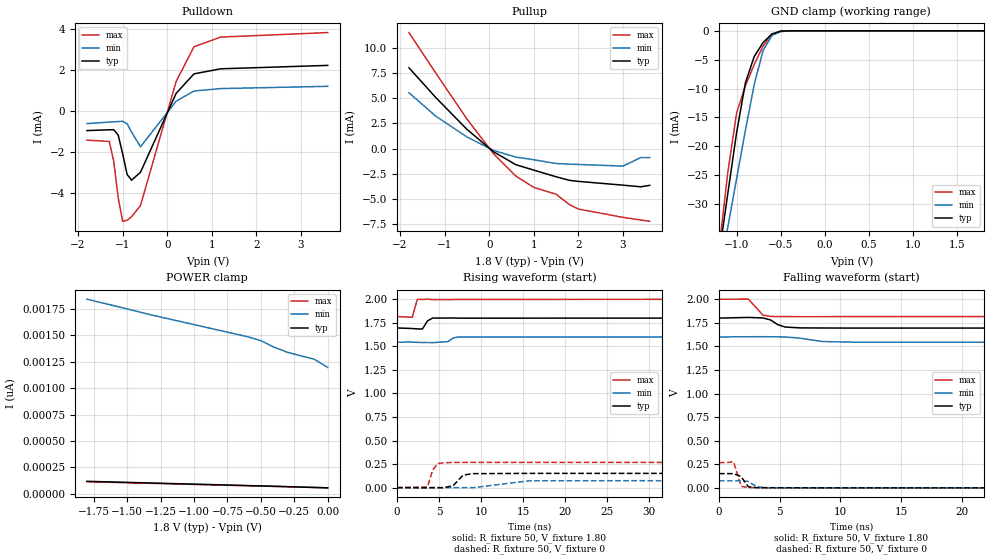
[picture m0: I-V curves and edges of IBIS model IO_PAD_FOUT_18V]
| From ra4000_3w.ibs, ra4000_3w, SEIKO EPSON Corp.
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[Model]   IO_PAD_FOUT_18V
Model_type 3-state
Enable Active-High
Polarity Non-Inverting
Vmeas=0.90
C_comp   2.5p   2.0p   3.0p
[Temperature Range] 25   125   -40
[Voltage Range]   1.80   1.60   2.00
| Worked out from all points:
|   slope of the pulldown table from 0 to 0.27 V, typ, clamps not added: 249 ohm
|   slope of the pullup table from 0 to 0.27 V, typ, clamps not added: 325 ohm
|   GND clamp passes 1 mA (typ) near -0.63 V on its own axis
|   falling waveform, R_fixture 50, V_fixture 1.80: 20-80 % time 939ps typ, 1.63ns min, 787ps max; typ from 1.8 V to 1.7 V
|   falling waveform, R_fixture 50, V_fixture 0: 20-80 % time 512ps typ, 605ps min, 376ps max; typ from 0.151 V to 0 V
|   rising waveform, R_fixture 50, V_fixture 1.80: 20-80 % time 568ps typ, 603ps min, 351ps max; typ from 1.7 V to 1.8 V
|   rising waveform, R_fixture 50, V_fixture 0: 20-80 % time 925ps typ, 1.58ns min, 705ps max; typ from 0 V to 0.151 V
[Pullup]
-1.8V     8.019mA    5.543mA    11.52mA
-1.2V     5.073mA    3.223mA    7.502mA
-500mV    1.91mA     1.152mA    2.939mA
100mV     -328.1uA   -184uA     -533.3uA
600mV     -1.606mA   -849uA     -2.738mA
1V        -2.14mA    -1.11mA    -3.857mA
1.5V      -2.802mA   -1.485mA   -4.534mA
1.8V      -3.153mA   -1.545mA   -5.569mA
2V        -3.258mA   -1.577mA   -6.004mA
3V        -3.633mA   -1.74mA    -6.831mA
3.4V      -3.796mA   -893.1uA   -7.094mA
3.6V      -3.649mA   -897.2uA   -7.222mA
[Pulldown]
-1.8V     -961.6uA   -619.2uA   -1.43mA
-1.3V     -922.8uA   -548.5uA   -1.492mA
-1.2V     -918.1uA   -534.5uA   -2.462mA
-1.1V     -1.178mA   -521.4uA   -4.238mA
-1V       -2.093mA   -509.6uA   -5.388mA
-900mV    -3.101mA   -625.5uA   -5.336mA
-800mV    -3.382mA   -1.035mA   -5.164mA
-600mV    -2.995mA   -1.753mA   -4.62mA
200mV     855.8uA    473.6uA    1.436mA
600mV     1.806mA    969.1uA    3.13mA
1.2V      2.053mA    1.088mA    3.601mA
3.6V      2.219mA    1.198mA    3.821mA
[GND Clamp]
-1.8V     -104.1mA   -95.66mA   -119.4mA
-1.2V     -38.93mA   -42.42mA   -37.91mA
-1.1V     -28.21mA   -33.99mA   -24.53mA
-1V       -17.61mA   -25.59mA   -14.2mA
-900mV    -8.983mA   -17.21mA   -9.508mA
-800mV    -4.448mA   -9.271mA   -5.815mA
-700mV    -2.032mA   -3.421mA   -2.638mA
-600mV    -545.3uA   -803.9uA   -605.9uA
-500mV    -56.89uA   -135.5uA   -35.53uA
-400mV    -3.147uA   -16.88uA   -734nA
1.8V      55.75pA    1.305nA    49.44pA
[POWER Clamp]
-1.8V     117.7pA    1.843nA    113.8pA
-1.3V     100.9pA    1.688nA    97.89pA
-600mV    77.54pA    1.487nA    75.68pA
-500mV    74.22pA    1.45nA     72.54pA
-400mV    70.76pA    1.387nA    69.39pA
-300mV    67.06pA    1.339nA    66.03pA
-100mV    59.63pA    1.273nA    59.28pA
0V        55.75pA    1.196nA    56.02pA
[Falling Waveform]
R_fixture=50
V_fixture=1.80
V_fixture_min=1.60
V_fixture_max=2.00
0s        1.8V       1.6V       2V
2.424ns   1.807V     1.602V     2.001V
3.636ns   1.801V     1.603V     1.83V
4.242ns   1.781V     1.601V     1.818V
4.848ns   1.73V      1.601V     1.816V
5.455ns   1.705V     1.6V       1.816V
6.667ns   1.696V     1.587V     1.815V
8.485ns   1.695V     1.552V     1.815V
10.91ns   1.694V     1.545V     1.816V
60ns      1.695V     1.544V     1.816V
[Falling Waveform]
R_fixture=50
V_fixture=0
V_fixture_min=0
V_fixture_max=0
0s        151.3mV    74.58mV    268mV
606.1ps   151.3mV    74.58mV    268mV
1.212ns   150.2mV    74.11mV    276.4mV
1.818ns   120.5mV    75.52mV    17.16mV
2.424ns   11.75mV    67.69mV    3.281mV
3.03ns    2.019mV    17.03mV    2.406mV
3.636ns   1.673mV    3.601mV    877.3uV
4.242ns   1.65mV     961.3uV    511.9uV
8.485ns   137.4uV    266.8uV    114.7uV
60ns      5.887uV    7.49uV     2.333uV
[Rising Waveform]
R_fixture=50
V_fixture=1.80
V_fixture_min=1.60
V_fixture_max=2.00
0s        1.695V     1.544V     1.816V
1.818ns   1.689V     1.545V     1.808V
2.424ns   1.685V     1.542V     1.999V
3.03ns    1.684V     1.541V     1.998V
3.636ns   1.77V      1.54V      2.001V
4.242ns   1.8V       1.539V     1.996V
6.061ns   1.8V       1.55V      1.997V
6.667ns   1.801V     1.587V     1.997V
7.273ns   1.799V     1.6V       1.998V
60ns      1.8V       1.6V       2V
[Rising Waveform]
R_fixture=50
V_fixture=0
V_fixture_min=0
V_fixture_max=0
0s        599pV      3.375nV    549pV
3.636ns   -2.591mV   38.29uV    7.967mV
4.242ns   23.5uV     28.61uV    184.9mV
4.848ns   -236.5uV   22.69uV    254.8mV
5.455ns   -833.2uV   -56.8uV    262.8mV
6.667ns   17.93mV    -1.272mV   266.7mV
7.879ns   133.3mV    9.801uV    267.6mV
9.091ns   148.2mV    -251uV     267.8mV
15.76ns   151.2mV    72.64mV    267.9mV
60ns      151.3mV    74.58mV    268mV
[Ramp]
R_load=50
dV/dt_r   9.075E-2/8.430E-10   4.475E-2/1.515E-9   1.608E-1/4.792E-10
dV/dt_f   6.318E-2/8.647E-10   3.338E-2/1.578E-9   1.106E-1/5.057E-10
|[End   IO_PAD_FOUT_18V
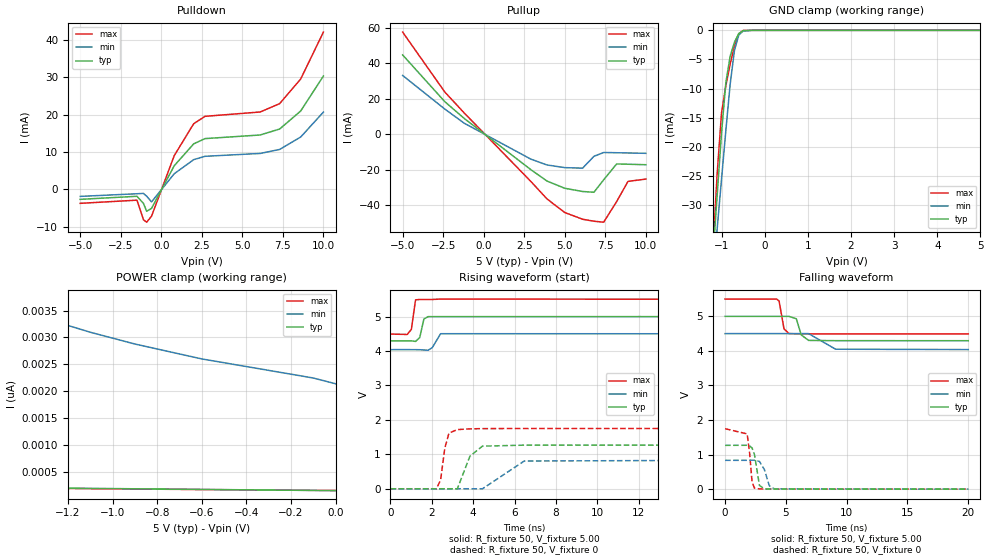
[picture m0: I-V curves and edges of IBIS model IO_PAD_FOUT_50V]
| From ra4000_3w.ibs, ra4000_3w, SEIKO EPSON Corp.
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[Model]   IO_PAD_FOUT_50V
Model_type 3-state
Enable Active-High
Polarity Non-Inverting
Vmeas=2.50
C_comp   2.5p   2.0p   3.0p
[Temperature Range] 25   125   -40
[Voltage Range]   5.00   4.50   5.50
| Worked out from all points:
|   slope of the pulldown table from 0 to 0.75 V, typ, clamps not added: 126 ohm
|   slope of the pullup table from 0 to 0.75 V, typ, clamps not added: 143 ohm
|   GND clamp passes 1 mA (typ) near -0.63 V on its own axis
|   falling waveform, R_fixture 50, V_fixture 5.00: 20-80 % time 401ps typ, 591ps min, 309ps max; typ from 5 V to 4.29 V
|   falling waveform, R_fixture 50, V_fixture 0: 20-80 % time 353ps typ, 464ps min, 298ps max; typ from 1.27 V to 0 V
|   rising waveform, R_fixture 50, V_fixture 5.00: 20-80 % time 158ps typ, 253ps min, 142ps max; typ from 4.29 V to 5 V
|   rising waveform, R_fixture 50, V_fixture 0: 20-80 % time 398ps typ, 603ps min, 283ps max; typ from 0 V to 1.27 V
[Pullup]
-5V       44.6mA     33.06mA    57.43mA
-2.4V     18.33mA    14.17mA    23.76mA
-1.2V     8.881mA    6.2mA      11.95mA
2.9V      -19.85mA   -13.95mA   -26.45mA
3.9V      -26.28mA   -17.26mA   -36.32mA
5V        -30.37mA   -18.76mA   -44mA
6.1V      -32.18mA   -19.06mA   -47.77mA
6.8V      -32.6mA    -12.39mA   -48.89mA
7.4V      -25.59mA   -10.25mA   -49.43mA
8.2V      -16.68mA   -10.39mA   -37.84mA
8.9V      -16.85mA   -10.51mA   -26.5mA
10V       -17.13mA   -10.72mA   -25.19mA
[Pulldown]
-5V       -2.695mA   -1.904mA   -3.76mA
-1.5V     -1.871mA   -1.196mA   -2.909mA
-1.1V     -3.756mA   -1.098mA   -8.145mA
-900mV    -5.868mA   -1.858mA   -8.805mA
-600mV    -5.116mA   -3.374mA   -7.202mA
800mV     6.302mA    4.159mA    9mA
2V        12.16mA    7.932mA    17.55mA
2.7V      13.56mA    8.824mA    19.52mA
6.1V      14.53mA    9.591mA    20.68mA
7.3V      16.12mA    10.66mA    22.91mA
8.6V      20.95mA    13.99mA    29.52mA
10V       30.3mA     20.65mA    42.06mA
[GND Clamp]
-5V       -507.1mA   -412.9mA   -622.2mA
-1.2V     -38.93mA   -42.42mA   -37.92mA
-1.1V     -28.22mA   -34mA      -24.54mA
-1V       -17.62mA   -25.59mA   -14.21mA
-900mV    -8.989mA   -17.22mA   -9.509mA
-800mV    -4.45mA    -9.278mA   -5.815mA
-700mV    -2.032mA   -3.427mA   -2.638mA
-600mV    -545.3uA   -804.8uA   -605.9uA
-500mV    -56.89uA   -135.5uA   -35.53uA
-300mV    -121.9nA   -1.69uA    -9.391nA
5V        151.4pA    2.52nA     136.9pA
[POWER Clamp]
-5V       441.4pA    19.15nA    8.229uA
-4.7V     412.4pA    16.71nA    4.235nA
-4.6V     403.3pA    15.96nA    343.3pA
-4.5V     394.5pA    15.24nA    298pA
-1.7V     219.2pA    3.963nA    206.5pA
-1.6V     214.7pA    3.794nA    203.4pA
-1.3V     201.7pA    3.349nA    193.8pA
-1.1V     193.4pA    3.097nA    187.4pA
-900mV    185.3pA    2.878nA    181pA
-600mV    173.6pA    2.601nA    171.5pA
-100mV    155.1pA    2.246nA    156.3pA
0V        151.4pA    2.139nA    153.5pA
[Falling Waveform]
R_fixture=50
V_fixture=5.00
V_fixture_min=4.50
V_fixture_max=5.50
0s        5V         4.5V       5.5V
4.242ns   5V         4.501V     5.5V
4.444ns   5V         4.5V       5.441V
4.848ns   5V         4.5V       4.638V
5.253ns   5V         4.5V       4.502V
5.859ns   4.93V      4.5V       4.494V
6.263ns   4.463V     4.5V       4.493V
6.869ns   4.304V     4.5V       4.493V
9.091ns   4.296V     4.049V     4.492V
20ns      4.295V     4.039V     4.492V
[Falling Waveform]
R_fixture=50
V_fixture=0
V_fixture_min=0
V_fixture_max=0
0s        1.268V     834.1mV    1.75V
1.818ns   1.27V      834.8mV    1.598V
2.02ns    1.252V     837mV      1.035V
2.222ns   1.192V     838.3mV    207.6mV
2.424ns   993.1mV    838.2mV    26.89mV
2.828ns   108.5mV    801.9mV    7.029mV
3.232ns   8.937mV    570.8mV    5.304mV
3.636ns   4.277mV    99.68mV    4.205mV
4.04ns    3.189mV    11.69mV    3.413mV
20ns      29.91uV    41.91uV    17.85uV
[Rising Waveform]
R_fixture=50
V_fixture=5.00
V_fixture_min=4.50
V_fixture_max=5.50
0s        4.295V     4.039V     4.492V
808.1ps   4.296V     4.04V      4.48V
1.01ns    4.293V     4.039V     4.626V
1.212ns   4.278V     4.039V     5.486V
1.414ns   4.389V     4.037V     5.495V
1.616ns   4.929V     4.029V     5.496V
1.818ns   4.997V     4.022V     5.497V
2.02ns    4.998V     4.097V     5.496V
2.424ns   4.998V     4.502V     5.508V
20ns      5V         4.5V       5.5V
[Rising Waveform]
R_fixture=50
V_fixture=0
V_fixture_min=0
V_fixture_max=0
0s        1.445nV    4.47nV     1.368nV
2.222ns   -891.5nV   -11.98mV   -1.444mV
2.424ns   48.18uV    -2.853mV   255.4mV
2.626ns   87.2uV     -183.6uV   1.179V
2.828ns   -294.4uV   -68.97uV   1.616V
3.232ns   -904uV     -22.36uV   1.718V
3.838ns   942.8mV    90.69uV    1.739V
4.444ns   1.237V     -999.9uV   1.746V
6.465ns   1.266V     805.1mV    1.749V
20ns      1.268V     834.1mV    1.75V
[Ramp]
R_load=50
dV/dt_r   7.608E-1/3.613E-10   5.004E-1/6.009E-10   1.050E+0/2.400E-10
dV/dt_f   4.228E-1/3.730E-10   2.767E-1/5.844E-10   6.049E-1/2.670E-10
|[End   IO_PAD_FOUT_50V
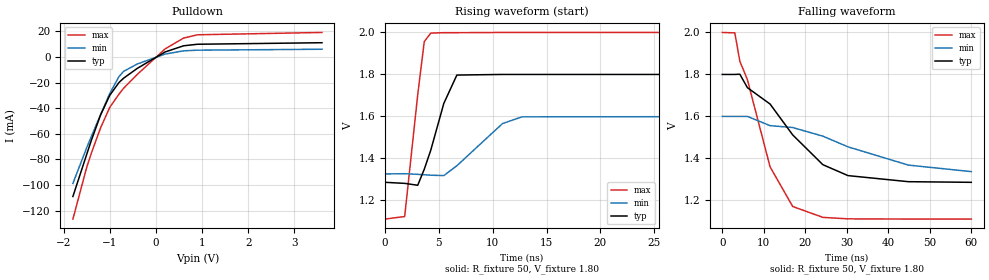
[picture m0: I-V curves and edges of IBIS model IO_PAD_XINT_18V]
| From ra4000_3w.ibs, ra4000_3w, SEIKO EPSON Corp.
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[Model]   IO_PAD_XINT_18V
Model_type Open_drain
Polarity Non-Inverting
Vref=2.0
Vmeas=0.9
Rref=5000
C_comp   2.5p   2.0p   3.0p
[Temperature Range] 25   125   -40
[Voltage Range]   1.80   1.60   2.00
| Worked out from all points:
|   slope of the pulldown table from 0 to 0.27 V, typ, clamps not added: 54.4 ohm
|   falling waveform, R_fixture 50, V_fixture 1.80: 20-80 % time 13.7ns typ, 23.5ns min, 7.76ns max; typ from 1.8 V to 1.29 V
|   rising waveform, R_fixture 50, V_fixture 1.80: 20-80 % time 1.8ns typ, 3.29ns min, 1.1ns max; typ from 1.29 V to 1.8 V
[Pulldown]
-1.8V     -108.9mA   -98.7mA    -126.5mA
-1.5V     -75.95mA   -70.76mA   -86.06mA
-1.4V     -65.08mA   -62.09mA   -75.07mA
-1.2V     -45.3mA    -45.03mA   -55.4mA
-1V       -29.91mA   -28.44mA   -39.28mA
-800mV    -19.93mA   -15.3mA    -29mA
-700mV    -16.58mA   -11.24mA   -24.44mA
-400mV    -8.853mA   -5.464mA   -13.51mA
200mV     3.863mA    2.205mA    6.265mA
600mV     8.675mA    4.737mA    14.69mA
900mV     9.873mA    5.241mA    17.26mA
3.6V      11.07mA    5.981mA    19.07mA
[Falling Waveform]
R_fixture=50
V_fixture=1.80
V_fixture_min=1.60
V_fixture_max=2.00
0s        1.8V       1.6V       2V
3.03ns    1.8V       1.6V       1.998V
4.242ns   1.801V     1.6V       1.863V
6.061ns   1.737V     1.6V       1.775V
11.52ns   1.659V     1.556V     1.36V
16.97ns   1.512V     1.547V     1.171V
24.24ns   1.37V      1.506V     1.119V
30.3ns    1.318V     1.455V     1.112V
44.85ns   1.289V     1.368V     1.111V
60ns      1.286V     1.337V     1.111V
[Rising Waveform]
R_fixture=50
V_fixture=1.80
V_fixture_min=1.60
V_fixture_max=2.00
0s        1.286V     1.326V     1.111V
1.818ns   1.281V     1.327V     1.123V
3.03ns    1.272V     1.324V     1.703V
3.636ns   1.348V     1.322V     1.956V
4.242ns   1.439V     1.32V      1.997V
5.455ns   1.662V     1.318V     1.999V
6.667ns   1.797V     1.365V     1.999V
10.91ns   1.8V       1.566V     2V
12.73ns   1.8V       1.598V     2V
60ns      1.8V       1.6V       2V
[Ramp]
R_load=50
dV/dt_r   3.085E-1/1.825E-9   1.642E-1/3.454E-9   5.334E-1/1.080E-9
dV/dt_f   3.084E-1/1.367E-8   1.579E-1/2.351E-8   5.334E-1/7.707E-9
|[End   IO_PAD_XINT_18V
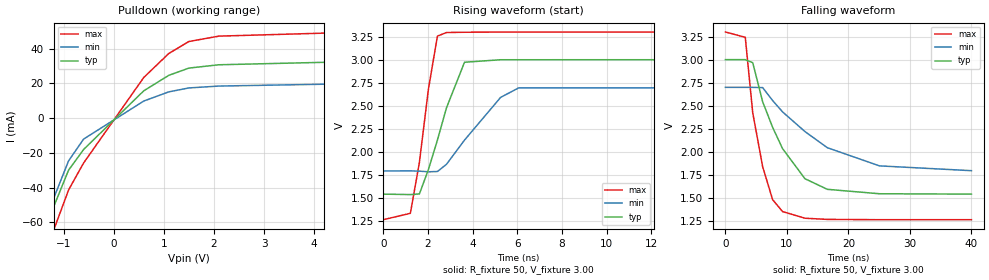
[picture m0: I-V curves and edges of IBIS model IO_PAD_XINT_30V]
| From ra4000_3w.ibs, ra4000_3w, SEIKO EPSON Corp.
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[Model]   IO_PAD_XINT_30V
Model_type Open_drain
Polarity Non-Inverting
Vref=3.3
Vmeas=1.5
Rref=5000
C_comp   2.5p   2.0p   3.0p
[Temperature Range] 25   125   -40
[Voltage Range]   3.00   2.70   3.30
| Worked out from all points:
|   slope of the pulldown table from 0 to 0.45 V, typ, clamps not added: 36.6 ohm
|   falling waveform, R_fixture 50, V_fixture 3.00: 20-80 % time 5.79ns typ, 10.4ns min, 2.99ns max; typ from 3 V to 1.54 V
|   rising waveform, R_fixture 50, V_fixture 3.00: 20-80 % time 1.08ns typ, 1.8ns min, 710ps max; typ from 1.54 V to 3 V
[Pulldown]
-3V       -260.3mA   -217.9mA   -314.6mA
-1.4V     -68.68mA   -63.46mA   -84.25mA
-1.3V     -59.72mA   -54.87mA   -74.25mA
-1.2V     -51.27mA   -46.4mA    -64.82mA
-900mV    -30mA      -24.64mA   -41.43mA
-600mV    -18.08mA   -12.07mA   -25.86mA
600mV     15.77mA    9.868mA    23.45mA
1.1V      24.7mA     15.17mA    37.31mA
1.5V      28.87mA    17.43mA    44.2mA
2.1V      30.79mA    18.51mA    47.31mA
5V        32.75mA    19.99mA    49.7mA
6V        34.91mA    21.45mA    52.66mA
[Falling Waveform]
R_fixture=50
V_fixture=3.00
V_fixture_min=2.70
V_fixture_max=3.30
0s        3V         2.7V       3.3V
3.232ns   3V         2.7V       3.242V
4.444ns   2.967V     2.7V       2.425V
6.061ns   2.543V     2.697V     1.839V
7.677ns   2.267V     2.557V     1.483V
9.293ns   2.036V     2.434V     1.354V
12.93ns   1.71V      2.221V     1.282V
16.57ns   1.595V     2.046V     1.269V
25.05ns   1.547V     1.849V     1.266V
40ns      1.543V     1.797V     1.266V
[Rising Waveform]
R_fixture=50
V_fixture=3.00
V_fixture_min=2.70
V_fixture_max=3.30
0s        1.543V     1.794V     1.266V
1.212ns   1.538V     1.795V     1.335V
1.616ns   1.545V     1.792V     1.886V
2.02ns    1.809V     1.785V     2.68V
2.424ns   2.129V     1.788V     3.255V
2.828ns   2.477V     1.866V     3.294V
3.636ns   2.972V     2.128V     3.297V
5.253ns   2.999V     2.591V     3.299V
6.061ns   2.999V     2.694V     3.299V
40ns      3V         2.7V       3.3V
[Ramp]
R_load=50
dV/dt_r   8.743E-1/1.061E-9   5.439E-1/1.833E-9   1.220E+0/6.505E-10
dV/dt_f   8.743E-1/5.792E-9   5.420E-1/1.038E-8   1.220E+0/2.997E-9
|[End   IO_PAD_XINT_30V
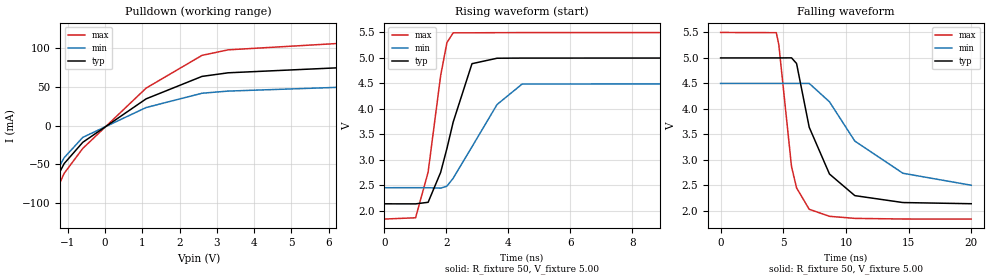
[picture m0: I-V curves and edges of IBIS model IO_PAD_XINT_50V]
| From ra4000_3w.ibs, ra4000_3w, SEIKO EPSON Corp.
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[Model]   IO_PAD_XINT_50V
Model_type Open_drain
Polarity Non-Inverting
Vref=5.5
Vmeas=2.5
Rref=5000
C_comp   2.5p   2.0p   3.0p
[Temperature Range] 25   125   -40
[Voltage Range]   5.00   4.50   5.50
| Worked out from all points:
|   slope of the pulldown table from 0 to 0.75 V, typ, clamps not added: 30.2 ohm
|   falling waveform, R_fixture 50, V_fixture 5.00: 20-80 % time 2.29ns typ, 4.45ns min, 1.11ns max; typ from 5 V to 2.14 V
|   rising waveform, R_fixture 50, V_fixture 5.00: 20-80 % time 741ps typ, 1.2ns min, 517ps max; typ from 2.14 V to 5 V
[Pulldown]
-5V       -520.2mA   -422.2mA   -640.6mA
-2.1V     -150.2mA   -131.1mA   -176.6mA
-2V       -137.7mA   -121.4mA   -161.3mA
-1.8V     -113.5mA   -101.8mA   -136.1mA
-1.1V     -48.86mA   -41.26mA   -61.43mA
-600mV    -21.34mA   -14.99mA   -29.25mA
1.1V      34.77mA    23.54mA    48.65mA
2.6V      63.75mA    42.01mA    90.93mA
3.3V      68.39mA    44.77mA    98.05mA
7.4V      77.39mA    51.54mA    109.5mA
8.8V      96.9mA     65.68mA    135.2mA
10V       126.3mA    87.31mA    173.8mA
[Falling Waveform]
R_fixture=50
V_fixture=5.00
V_fixture_min=4.50
V_fixture_max=5.50
0s        5V         4.5V       5.5V
4.444ns   5V         4.5V       5.496V
4.646ns   5V         4.5V       5.257V
5.657ns   5.002V     4.5V       2.87V
6.061ns   4.891V     4.5V       2.449V
7.071ns   3.639V     4.5V       2.029V
8.687ns   2.721V     4.139V     1.891V
10.71ns   2.297V     3.368V     1.85V
14.55ns   2.161V     2.736V     1.838V
20ns      2.138V     2.501V     1.837V
[Rising Waveform]
R_fixture=50
V_fixture=5.00
V_fixture_min=4.50
V_fixture_max=5.50
0s        2.136V     2.452V     1.837V
1.01ns    2.135V     2.453V     1.862V
1.414ns   2.166V     2.452V     2.758V
1.818ns   2.754V     2.444V     4.654V
2.02ns    3.222V     2.482V     5.301V
2.222ns   3.741V     2.639V     5.493V
2.828ns   4.887V     3.255V     5.493V
3.636ns   4.994V     4.085V     5.496V
4.444ns   4.997V     4.487V     5.497V
20ns      5V         4.5V       5.5V
[Ramp]
R_load=50
dV/dt_r   1.719E+0/7.274E-10   1.229E+0/1.200E-9   2.198E+0/4.900E-10
dV/dt_f   1.717E+0/2.290E-9   1.199E+0/4.455E-9   2.198E+0/1.097E-9
|[End   IO_PAD_XINT_50V
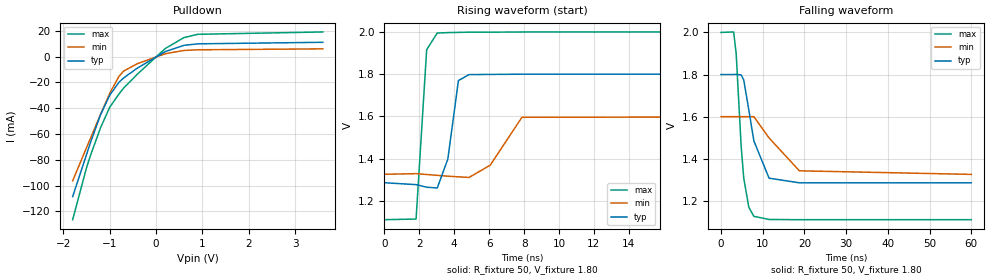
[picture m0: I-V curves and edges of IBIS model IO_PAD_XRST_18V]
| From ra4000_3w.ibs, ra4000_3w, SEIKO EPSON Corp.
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[Model]   IO_PAD_XRST_18V
Model_type Open_drain
Polarity Non-Inverting
Vref=2.0
Vmeas=0.9
Rref=5000
C_comp   2.5p   2.0p   3.0p
[Temperature Range] 25   125   -40
[Voltage Range]   1.80   1.60   2.00
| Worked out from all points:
|   slope of the pulldown table from 0 to 0.27 V, typ, clamps not added: 54.4 ohm
|   falling waveform, R_fixture 50, V_fixture 1.80: 20-80 % time 2.9ns typ, 5.02ns min, 1.75ns max; typ from 1.8 V to 1.29 V
|   rising waveform, R_fixture 50, V_fixture 1.80: 20-80 % time 529ps typ, 1.16ns min, 403ps max; typ from 1.29 V to 1.8 V
[Pulldown]
-1.8V     -108.6mA   -96.32mA   -126.5mA
-1.5V     -75.94mA   -70.59mA   -86.06mA
-1.4V     -65.08mA   -62.05mA   -75.07mA
-1.2V     -45.3mA    -45.03mA   -55.4mA
-1V       -29.91mA   -28.44mA   -39.28mA
-800mV    -19.93mA   -15.3mA    -29mA
-700mV    -16.58mA   -11.24mA   -24.44mA
-400mV    -8.853mA   -5.464mA   -13.51mA
200mV     3.863mA    2.205mA    6.265mA
600mV     8.675mA    4.737mA    14.69mA
900mV     9.873mA    5.241mA    17.26mA
3.6V      11.07mA    5.981mA    19.07mA
[Falling Waveform]
R_fixture=50
V_fixture=1.80
V_fixture_min=1.60
V_fixture_max=2.00
0s        1.8V       1.6V       2V
3.03ns    1.8V       1.6V       2.002V
3.636ns   1.801V     1.6V       1.899V
4.848ns   1.798V     1.6V       1.454V
5.455ns   1.774V     1.6V       1.308V
6.667ns   1.632V     1.6V       1.17V
7.879ns   1.485V     1.6V       1.127V
11.52ns   1.308V     1.499V     1.112V
18.79ns   1.286V     1.343V     1.111V
60ns      1.286V     1.326V     1.111V
[Rising Waveform]
R_fixture=50
V_fixture=1.80
V_fixture_min=1.60
V_fixture_max=2.00
0s        1.286V     1.326V     1.111V
1.818ns   1.277V     1.329V     1.114V
2.424ns   1.265V     1.325V     1.916V
3.03ns    1.261V     1.321V     1.995V
3.636ns   1.398V     1.317V     1.997V
4.242ns   1.77V      1.314V     1.998V
4.848ns   1.798V     1.311V     1.999V
6.061ns   1.799V     1.369V     1.999V
7.879ns   1.8V       1.596V     2V
60ns      1.8V       1.6V       2V
[Ramp]
R_load=50
dV/dt_r   3.085E-1/4.500E-10   1.642E-1/1.134E-9   5.334E-1/3.056E-10
dV/dt_f   3.085E-1/2.896E-9   1.642E-1/5.002E-9   5.334E-1/1.723E-9
|[End   IO_PAD_XRST_18V
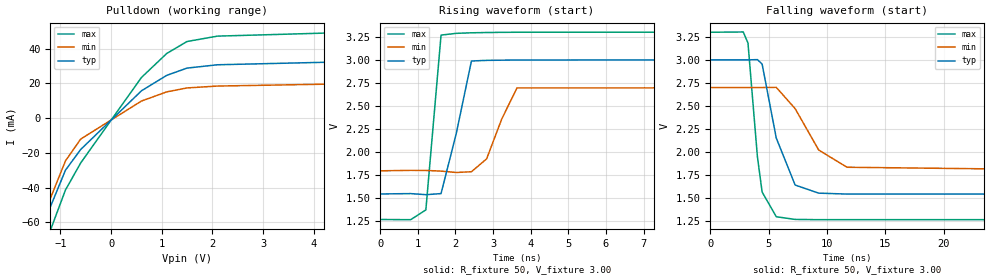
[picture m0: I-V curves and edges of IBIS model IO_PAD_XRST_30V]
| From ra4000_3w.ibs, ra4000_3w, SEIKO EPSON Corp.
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[Model]   IO_PAD_XRST_30V
Model_type Open_drain
Polarity Non-Inverting
Vref=3.3
Vmeas=1.5
Rref=5000
C_comp   2.5p   2.0p   3.0p
[Temperature Range] 25   125   -40
[Voltage Range]   3.00   2.70   3.30
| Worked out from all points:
|   slope of the pulldown table from 0 to 0.45 V, typ, clamps not added: 36.6 ohm
|   falling waveform, R_fixture 50, V_fixture 3.00: 20-80 % time 1.53ns typ, 2.57ns min, 918ps max; typ from 3 V to 1.54 V
|   rising waveform, R_fixture 50, V_fixture 3.00: 20-80 % time 488ps typ, 551ps min, 260ps max; typ from 1.54 V to 3 V
[Pulldown]
-3V       -244.2mA   -202.6mA   -296.9mA
-1.4V     -68.68mA   -63.41mA   -84.25mA
-1.3V     -59.72mA   -54.86mA   -74.25mA
-1.2V     -51.27mA   -46.4mA    -64.82mA
-900mV    -30mA      -24.64mA   -41.43mA
-600mV    -18.08mA   -12.07mA   -25.86mA
600mV     15.77mA    9.868mA    23.45mA
1.1V      24.7mA     15.17mA    37.31mA
1.5V      28.87mA    17.43mA    44.2mA
2.1V      30.79mA    18.51mA    47.31mA
5V        32.75mA    19.99mA    49.7mA
6V        34.91mA    21.45mA    52.66mA
[Falling Waveform]
R_fixture=50
V_fixture=3.00
V_fixture_min=2.70
V_fixture_max=3.30
0s        3V         2.7V       3.3V
2.828ns   3V         2.7V       3.303V
3.232ns   3V         2.7V       3.183V
4.04ns    3.003V     2.7V       1.949V
4.444ns   2.955V     2.7V       1.566V
5.657ns   2.151V     2.702V     1.298V
7.273ns   1.642V     2.471V     1.269V
9.293ns   1.554V     2.022V     1.266V
11.72ns   1.544V     1.835V     1.266V
40ns      1.543V     1.794V     1.266V
[Rising Waveform]
R_fixture=50
V_fixture=3.00
V_fixture_min=2.70
V_fixture_max=3.30
0s        1.543V     1.794V     1.266V
808.1ps   1.547V     1.799V     1.264V
1.212ns   1.535V     1.798V     1.37V
1.616ns   1.547V     1.791V     3.266V
2.02ns    2.198V     1.776V     3.285V
2.424ns   2.985V     1.784V     3.291V
2.828ns   2.992V     1.924V     3.294V
3.232ns   2.994V     2.358V     3.296V
3.636ns   2.996V     2.693V     3.297V
40ns      3V         2.7V       3.3V
[Ramp]
R_load=50
dV/dt_r   8.743E-1/2.876E-10   5.439E-1/4.875E-10   1.220E+0/1.754E-10
dV/dt_f   8.743E-1/1.516E-9   5.439E-1/2.563E-9   1.220E+0/8.753E-10
|[End   IO_PAD_XRST_30V
